VERSION 5.7 ;
  NOWIREEXTENSIONATPIN ON ;
  DIVIDERCHAR "/" ;
  BUSBITCHARS "[]" ;
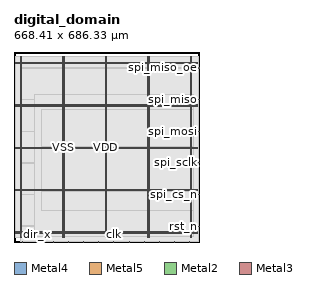
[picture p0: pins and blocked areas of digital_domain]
MACRO digital_domain
  CLASS BLOCK ;
  FOREIGN digital_domain ;
  ORIGIN 0.000 0.000 ;
  SIZE 668.410 BY 686.330 ;
  PIN VDD
    DIRECTION INOUT ;
    USE POWER ;
    PORT
      LAYER Metal4 ;
        RECT 22.240 15.380 23.840 670.620 ;
    END
    PORT
      LAYER Metal4 ;
        RECT 175.840 15.380 177.440 670.620 ;
    END
    PORT
      LAYER Metal4 ;
        RECT 329.440 15.380 331.040 670.620 ;
    END
    PORT
      LAYER Metal4 ;
        RECT 483.040 15.380 484.640 670.620 ;
    END
    PORT
      LAYER Metal4 ;
        RECT 636.640 15.380 638.240 670.620 ;
    END
    PORT
      LAYER Metal5 ;
        RECT 6.720 31.530 661.360 33.130 ;
    END
    PORT
      LAYER Metal5 ;
        RECT 6.720 184.710 661.360 186.310 ;
    END
    PORT
      LAYER Metal5 ;
        RECT 6.720 337.890 661.360 339.490 ;
    END
    PORT
      LAYER Metal5 ;
        RECT 6.720 491.070 661.360 492.670 ;
    END
    PORT
      LAYER Metal5 ;
        RECT 6.720 644.250 661.360 645.850 ;
    END
  END VDD
  PIN VSS
    DIRECTION INOUT ;
    USE GROUND ;
    PORT
      LAYER Metal4 ;
        RECT 25.540 15.380 27.140 670.620 ;
    END
    PORT
      LAYER Metal4 ;
        RECT 179.140 15.380 180.740 670.620 ;
    END
    PORT
      LAYER Metal4 ;
        RECT 332.740 15.380 334.340 670.620 ;
    END
    PORT
      LAYER Metal4 ;
        RECT 486.340 15.380 487.940 670.620 ;
    END
    PORT
      LAYER Metal4 ;
        RECT 639.940 15.380 641.540 670.620 ;
    END
    PORT
      LAYER Metal5 ;
        RECT 6.720 34.830 661.360 36.430 ;
    END
    PORT
      LAYER Metal5 ;
        RECT 6.720 188.010 661.360 189.610 ;
    END
    PORT
      LAYER Metal5 ;
        RECT 6.720 341.190 661.360 342.790 ;
    END
    PORT
      LAYER Metal5 ;
        RECT 6.720 494.370 661.360 495.970 ;
    END
    PORT
      LAYER Metal5 ;
        RECT 6.720 647.550 661.360 649.150 ;
    END
  END VSS
  PIN clk
    DIRECTION INPUT ;
    USE SIGNAL ;
    ANTENNAGATEAREA 4.738000 ;
    PORT
      LAYER Metal2 ;
        RECT 360.640 0.000 361.200 0.560 ;
    END
  END clk
  PIN comp_x
    DIRECTION INPUT ;
    USE SIGNAL ;
    ANTENNAGATEAREA 0.498500 ;
    PORT
      LAYER Metal2 ;
        RECT 250.880 0.000 251.440 0.560 ;
    END
  END comp_x
  PIN comp_y
    DIRECTION INPUT ;
    USE SIGNAL ;
    ANTENNAGATEAREA 0.498500 ;
    PORT
      LAYER Metal2 ;
        RECT 415.520 0.000 416.080 0.560 ;
    END
  END comp_y
  PIN dir_x
    DIRECTION OUTPUT ;
    USE SIGNAL ;
    ANTENNADIFFAREA 1.182800 ;
    PORT
      LAYER Metal2 ;
        RECT 86.240 0.000 86.800 0.560 ;
    END
  END dir_x
  PIN dir_y
    DIRECTION OUTPUT ;
    USE SIGNAL ;
    ANTENNADIFFAREA 1.182800 ;
    PORT
      LAYER Metal2 ;
        RECT 580.160 0.000 580.720 0.560 ;
    END
  END dir_y
  PIN mems_drv_x
    DIRECTION OUTPUT ;
    USE SIGNAL ;
    ANTENNADIFFAREA 1.182800 ;
    PORT
      LAYER Metal2 ;
        RECT 141.120 0.000 141.680 0.560 ;
    END
  END mems_drv_x
  PIN mems_drv_y
    DIRECTION OUTPUT ;
    USE SIGNAL ;
    ANTENNADIFFAREA 1.182800 ;
    PORT
      LAYER Metal2 ;
        RECT 525.280 0.000 525.840 0.560 ;
    END
  END mems_drv_y
  PIN move_en_x
    DIRECTION OUTPUT ;
    USE SIGNAL ;
    ANTENNADIFFAREA 1.182800 ;
    PORT
      LAYER Metal2 ;
        RECT 31.360 0.000 31.920 0.560 ;
    END
  END move_en_x
  PIN move_en_y
    DIRECTION OUTPUT ;
    USE SIGNAL ;
    ANTENNADIFFAREA 1.182800 ;
    PORT
      LAYER Metal2 ;
        RECT 635.040 0.000 635.600 0.560 ;
    END
  END move_en_y
  PIN read_en
    DIRECTION OUTPUT ;
    USE SIGNAL ;
    ANTENNADIFFAREA 1.182800 ;
    PORT
      LAYER Metal2 ;
        RECT 305.760 0.000 306.320 0.560 ;
    END
  END read_en
  PIN ref_wave_x
    DIRECTION OUTPUT ;
    USE SIGNAL ;
    ANTENNADIFFAREA 1.182800 ;
    PORT
      LAYER Metal2 ;
        RECT 196.000 0.000 196.560 0.560 ;
    END
  END ref_wave_x
  PIN ref_wave_y
    DIRECTION OUTPUT ;
    USE SIGNAL ;
    ANTENNADIFFAREA 1.182800 ;
    PORT
      LAYER Metal2 ;
        RECT 470.400 0.000 470.960 0.560 ;
    END
  END ref_wave_y
  PIN rst_n
    DIRECTION INPUT ;
    USE SIGNAL ;
    ANTENNAGATEAREA 0.498500 ;
    PORT
      LAYER Metal3 ;
        RECT 667.850 57.120 668.410 57.680 ;
    END
  END rst_n
  PIN spi_cs_n
    DIRECTION INPUT ;
    USE SIGNAL ;
    ANTENNAGATEAREA 0.498500 ;
    PORT
      LAYER Metal3 ;
        RECT 667.850 171.360 668.410 171.920 ;
    END
  END spi_cs_n
  PIN spi_miso
    DIRECTION OUTPUT ;
    USE SIGNAL ;
    ANTENNADIFFAREA 1.182800 ;
    PORT
      LAYER Metal3 ;
        RECT 667.850 514.080 668.410 514.640 ;
    END
  END spi_miso
  PIN spi_miso_oe
    DIRECTION OUTPUT ;
    USE SIGNAL ;
    ANTENNADIFFAREA 1.182800 ;
    PORT
      LAYER Metal3 ;
        RECT 667.850 628.320 668.410 628.880 ;
    END
  END spi_miso_oe
  PIN spi_mosi
    DIRECTION INPUT ;
    USE SIGNAL ;
    ANTENNAGATEAREA 0.498500 ;
    PORT
      LAYER Metal3 ;
        RECT 667.850 399.840 668.410 400.400 ;
    END
  END spi_mosi
  PIN spi_sclk
    DIRECTION INPUT ;
    USE SIGNAL ;
    ANTENNAGATEAREA 0.498500 ;
    PORT
      LAYER Metal3 ;
        RECT 667.850 285.600 668.410 286.160 ;
    END
  END spi_sclk
  OBS
      LAYER Nwell ;
        RECT 6.290 668.160 661.790 670.750 ;
      LAYER Pwell ;
        RECT 6.290 664.640 661.790 668.160 ;
      LAYER Nwell ;
        RECT 6.290 660.320 661.790 664.640 ;
      LAYER Pwell ;
        RECT 6.290 656.800 661.790 660.320 ;
      LAYER Nwell ;
        RECT 6.290 652.480 661.790 656.800 ;
      LAYER Pwell ;
        RECT 6.290 648.960 661.790 652.480 ;
      LAYER Nwell ;
        RECT 6.290 644.640 661.790 648.960 ;
      LAYER Pwell ;
        RECT 6.290 641.120 661.790 644.640 ;
      LAYER Nwell ;
        RECT 6.290 636.800 661.790 641.120 ;
      LAYER Pwell ;
        RECT 6.290 633.280 661.790 636.800 ;
      LAYER Nwell ;
        RECT 6.290 628.960 661.790 633.280 ;
      LAYER Pwell ;
        RECT 6.290 625.440 661.790 628.960 ;
      LAYER Nwell ;
        RECT 6.290 621.120 661.790 625.440 ;
      LAYER Pwell ;
        RECT 6.290 617.600 661.790 621.120 ;
      LAYER Nwell ;
        RECT 6.290 613.280 661.790 617.600 ;
      LAYER Pwell ;
        RECT 6.290 609.760 661.790 613.280 ;
      LAYER Nwell ;
        RECT 6.290 605.440 661.790 609.760 ;
      LAYER Pwell ;
        RECT 6.290 601.920 661.790 605.440 ;
      LAYER Nwell ;
        RECT 6.290 597.600 661.790 601.920 ;
      LAYER Pwell ;
        RECT 6.290 594.080 661.790 597.600 ;
      LAYER Nwell ;
        RECT 6.290 589.760 661.790 594.080 ;
      LAYER Pwell ;
        RECT 6.290 586.240 661.790 589.760 ;
      LAYER Nwell ;
        RECT 6.290 581.920 661.790 586.240 ;
      LAYER Pwell ;
        RECT 6.290 578.400 661.790 581.920 ;
      LAYER Nwell ;
        RECT 6.290 574.080 661.790 578.400 ;
      LAYER Pwell ;
        RECT 6.290 570.560 661.790 574.080 ;
      LAYER Nwell ;
        RECT 6.290 566.240 661.790 570.560 ;
      LAYER Pwell ;
        RECT 6.290 562.720 661.790 566.240 ;
      LAYER Nwell ;
        RECT 6.290 558.400 661.790 562.720 ;
      LAYER Pwell ;
        RECT 6.290 554.880 661.790 558.400 ;
      LAYER Nwell ;
        RECT 6.290 550.560 661.790 554.880 ;
      LAYER Pwell ;
        RECT 6.290 547.040 661.790 550.560 ;
      LAYER Nwell ;
        RECT 6.290 542.720 661.790 547.040 ;
      LAYER Pwell ;
        RECT 6.290 539.200 661.790 542.720 ;
      LAYER Nwell ;
        RECT 6.290 534.880 661.790 539.200 ;
      LAYER Pwell ;
        RECT 6.290 531.360 661.790 534.880 ;
      LAYER Nwell ;
        RECT 6.290 527.040 661.790 531.360 ;
      LAYER Pwell ;
        RECT 6.290 523.520 661.790 527.040 ;
      LAYER Nwell ;
        RECT 6.290 519.200 661.790 523.520 ;
      LAYER Pwell ;
        RECT 6.290 515.680 661.790 519.200 ;
      LAYER Nwell ;
        RECT 6.290 511.360 661.790 515.680 ;
      LAYER Pwell ;
        RECT 6.290 507.840 661.790 511.360 ;
      LAYER Nwell ;
        RECT 6.290 503.520 661.790 507.840 ;
      LAYER Pwell ;
        RECT 6.290 500.000 661.790 503.520 ;
      LAYER Nwell ;
        RECT 6.290 495.680 661.790 500.000 ;
      LAYER Pwell ;
        RECT 6.290 492.160 661.790 495.680 ;
      LAYER Nwell ;
        RECT 6.290 487.840 661.790 492.160 ;
      LAYER Pwell ;
        RECT 6.290 484.320 661.790 487.840 ;
      LAYER Nwell ;
        RECT 6.290 480.000 661.790 484.320 ;
      LAYER Pwell ;
        RECT 6.290 476.480 661.790 480.000 ;
      LAYER Nwell ;
        RECT 6.290 472.160 661.790 476.480 ;
      LAYER Pwell ;
        RECT 6.290 468.640 661.790 472.160 ;
      LAYER Nwell ;
        RECT 6.290 464.320 661.790 468.640 ;
      LAYER Pwell ;
        RECT 6.290 460.800 661.790 464.320 ;
      LAYER Nwell ;
        RECT 6.290 456.480 661.790 460.800 ;
      LAYER Pwell ;
        RECT 6.290 452.960 661.790 456.480 ;
      LAYER Nwell ;
        RECT 6.290 448.640 661.790 452.960 ;
      LAYER Pwell ;
        RECT 6.290 445.120 661.790 448.640 ;
      LAYER Nwell ;
        RECT 6.290 440.800 661.790 445.120 ;
      LAYER Pwell ;
        RECT 6.290 437.280 661.790 440.800 ;
      LAYER Nwell ;
        RECT 6.290 432.960 661.790 437.280 ;
      LAYER Pwell ;
        RECT 6.290 429.440 661.790 432.960 ;
      LAYER Nwell ;
        RECT 6.290 425.120 661.790 429.440 ;
      LAYER Pwell ;
        RECT 6.290 421.600 661.790 425.120 ;
      LAYER Nwell ;
        RECT 6.290 417.280 661.790 421.600 ;
      LAYER Pwell ;
        RECT 6.290 413.760 661.790 417.280 ;
      LAYER Nwell ;
        RECT 6.290 409.440 661.790 413.760 ;
      LAYER Pwell ;
        RECT 6.290 405.920 661.790 409.440 ;
      LAYER Nwell ;
        RECT 6.290 401.600 661.790 405.920 ;
      LAYER Pwell ;
        RECT 6.290 398.080 661.790 401.600 ;
      LAYER Nwell ;
        RECT 6.290 393.760 661.790 398.080 ;
      LAYER Pwell ;
        RECT 6.290 390.240 661.790 393.760 ;
      LAYER Nwell ;
        RECT 6.290 385.920 661.790 390.240 ;
      LAYER Pwell ;
        RECT 6.290 382.400 661.790 385.920 ;
      LAYER Nwell ;
        RECT 6.290 378.080 661.790 382.400 ;
      LAYER Pwell ;
        RECT 6.290 374.560 661.790 378.080 ;
      LAYER Nwell ;
        RECT 6.290 370.240 661.790 374.560 ;
      LAYER Pwell ;
        RECT 6.290 366.720 661.790 370.240 ;
      LAYER Nwell ;
        RECT 6.290 362.400 661.790 366.720 ;
      LAYER Pwell ;
        RECT 6.290 358.880 661.790 362.400 ;
      LAYER Nwell ;
        RECT 6.290 354.560 661.790 358.880 ;
      LAYER Pwell ;
        RECT 6.290 351.040 661.790 354.560 ;
      LAYER Nwell ;
        RECT 6.290 346.720 661.790 351.040 ;
      LAYER Pwell ;
        RECT 6.290 343.200 661.790 346.720 ;
      LAYER Nwell ;
        RECT 6.290 338.880 661.790 343.200 ;
      LAYER Pwell ;
        RECT 6.290 335.360 661.790 338.880 ;
      LAYER Nwell ;
        RECT 6.290 331.040 661.790 335.360 ;
      LAYER Pwell ;
        RECT 6.290 327.520 661.790 331.040 ;
      LAYER Nwell ;
        RECT 6.290 323.200 661.790 327.520 ;
      LAYER Pwell ;
        RECT 6.290 319.680 661.790 323.200 ;
      LAYER Nwell ;
        RECT 6.290 315.360 661.790 319.680 ;
      LAYER Pwell ;
        RECT 6.290 311.840 661.790 315.360 ;
      LAYER Nwell ;
        RECT 6.290 307.520 661.790 311.840 ;
      LAYER Pwell ;
        RECT 6.290 304.000 661.790 307.520 ;
      LAYER Nwell ;
        RECT 6.290 299.680 661.790 304.000 ;
      LAYER Pwell ;
        RECT 6.290 296.160 661.790 299.680 ;
      LAYER Nwell ;
        RECT 6.290 291.840 661.790 296.160 ;
      LAYER Pwell ;
        RECT 6.290 288.320 661.790 291.840 ;
      LAYER Nwell ;
        RECT 6.290 284.000 661.790 288.320 ;
      LAYER Pwell ;
        RECT 6.290 280.480 661.790 284.000 ;
      LAYER Nwell ;
        RECT 6.290 276.160 661.790 280.480 ;
      LAYER Pwell ;
        RECT 6.290 272.640 661.790 276.160 ;
      LAYER Nwell ;
        RECT 6.290 268.320 661.790 272.640 ;
      LAYER Pwell ;
        RECT 6.290 264.800 661.790 268.320 ;
      LAYER Nwell ;
        RECT 6.290 260.480 661.790 264.800 ;
      LAYER Pwell ;
        RECT 6.290 256.960 661.790 260.480 ;
      LAYER Nwell ;
        RECT 6.290 252.640 661.790 256.960 ;
      LAYER Pwell ;
        RECT 6.290 249.120 661.790 252.640 ;
      LAYER Nwell ;
        RECT 6.290 244.800 661.790 249.120 ;
      LAYER Pwell ;
        RECT 6.290 241.280 661.790 244.800 ;
      LAYER Nwell ;
        RECT 6.290 236.960 661.790 241.280 ;
      LAYER Pwell ;
        RECT 6.290 233.440 661.790 236.960 ;
      LAYER Nwell ;
        RECT 6.290 229.120 661.790 233.440 ;
      LAYER Pwell ;
        RECT 6.290 225.600 661.790 229.120 ;
      LAYER Nwell ;
        RECT 6.290 221.280 661.790 225.600 ;
      LAYER Pwell ;
        RECT 6.290 217.760 661.790 221.280 ;
      LAYER Nwell ;
        RECT 6.290 213.440 661.790 217.760 ;
      LAYER Pwell ;
        RECT 6.290 209.920 661.790 213.440 ;
      LAYER Nwell ;
        RECT 6.290 205.600 661.790 209.920 ;
      LAYER Pwell ;
        RECT 6.290 202.080 661.790 205.600 ;
      LAYER Nwell ;
        RECT 6.290 197.760 661.790 202.080 ;
      LAYER Pwell ;
        RECT 6.290 194.240 661.790 197.760 ;
      LAYER Nwell ;
        RECT 6.290 189.920 661.790 194.240 ;
      LAYER Pwell ;
        RECT 6.290 186.400 661.790 189.920 ;
      LAYER Nwell ;
        RECT 6.290 182.080 661.790 186.400 ;
      LAYER Pwell ;
        RECT 6.290 178.560 661.790 182.080 ;
      LAYER Nwell ;
        RECT 6.290 174.240 661.790 178.560 ;
      LAYER Pwell ;
        RECT 6.290 170.720 661.790 174.240 ;
      LAYER Nwell ;
        RECT 6.290 166.400 661.790 170.720 ;
      LAYER Pwell ;
        RECT 6.290 162.880 661.790 166.400 ;
      LAYER Nwell ;
        RECT 6.290 158.560 661.790 162.880 ;
      LAYER Pwell ;
        RECT 6.290 155.040 661.790 158.560 ;
      LAYER Nwell ;
        RECT 6.290 150.720 661.790 155.040 ;
      LAYER Pwell ;
        RECT 6.290 147.200 661.790 150.720 ;
      LAYER Nwell ;
        RECT 6.290 142.880 661.790 147.200 ;
      LAYER Pwell ;
        RECT 6.290 139.360 661.790 142.880 ;
      LAYER Nwell ;
        RECT 6.290 135.040 661.790 139.360 ;
      LAYER Pwell ;
        RECT 6.290 131.520 661.790 135.040 ;
      LAYER Nwell ;
        RECT 6.290 127.200 661.790 131.520 ;
      LAYER Pwell ;
        RECT 6.290 123.680 661.790 127.200 ;
      LAYER Nwell ;
        RECT 6.290 119.360 661.790 123.680 ;
      LAYER Pwell ;
        RECT 6.290 115.840 661.790 119.360 ;
      LAYER Nwell ;
        RECT 6.290 111.520 661.790 115.840 ;
      LAYER Pwell ;
        RECT 6.290 108.000 661.790 111.520 ;
      LAYER Nwell ;
        RECT 6.290 103.680 661.790 108.000 ;
      LAYER Pwell ;
        RECT 6.290 100.160 661.790 103.680 ;
      LAYER Nwell ;
        RECT 6.290 95.840 661.790 100.160 ;
      LAYER Pwell ;
        RECT 6.290 92.320 661.790 95.840 ;
      LAYER Nwell ;
        RECT 6.290 88.000 661.790 92.320 ;
      LAYER Pwell ;
        RECT 6.290 84.480 661.790 88.000 ;
      LAYER Nwell ;
        RECT 6.290 80.160 661.790 84.480 ;
      LAYER Pwell ;
        RECT 6.290 76.640 661.790 80.160 ;
      LAYER Nwell ;
        RECT 6.290 72.320 661.790 76.640 ;
      LAYER Pwell ;
        RECT 6.290 68.800 661.790 72.320 ;
      LAYER Nwell ;
        RECT 6.290 64.480 661.790 68.800 ;
      LAYER Pwell ;
        RECT 6.290 60.960 661.790 64.480 ;
      LAYER Nwell ;
        RECT 6.290 56.640 661.790 60.960 ;
      LAYER Pwell ;
        RECT 6.290 53.120 661.790 56.640 ;
      LAYER Nwell ;
        RECT 6.290 48.800 661.790 53.120 ;
      LAYER Pwell ;
        RECT 6.290 45.280 661.790 48.800 ;
      LAYER Nwell ;
        RECT 6.290 40.960 661.790 45.280 ;
      LAYER Pwell ;
        RECT 6.290 37.440 661.790 40.960 ;
      LAYER Nwell ;
        RECT 6.290 33.120 661.790 37.440 ;
      LAYER Pwell ;
        RECT 6.290 29.600 661.790 33.120 ;
      LAYER Nwell ;
        RECT 6.290 25.280 661.790 29.600 ;
      LAYER Pwell ;
        RECT 6.290 21.760 661.790 25.280 ;
      LAYER Nwell ;
        RECT 6.290 17.440 661.790 21.760 ;
      LAYER Pwell ;
        RECT 6.290 15.250 661.790 17.440 ;
      LAYER Metal1 ;
        RECT 6.720 15.380 661.360 670.620 ;
      LAYER Metal2 ;
        RECT 22.380 0.860 660.660 670.510 ;
        RECT 22.380 0.140 31.060 0.860 ;
        RECT 32.220 0.140 85.940 0.860 ;
        RECT 87.100 0.140 140.820 0.860 ;
        RECT 141.980 0.140 195.700 0.860 ;
        RECT 196.860 0.140 250.580 0.860 ;
        RECT 251.740 0.140 305.460 0.860 ;
        RECT 306.620 0.140 360.340 0.860 ;
        RECT 361.500 0.140 415.220 0.860 ;
        RECT 416.380 0.140 470.100 0.860 ;
        RECT 471.260 0.140 524.980 0.860 ;
        RECT 526.140 0.140 579.860 0.860 ;
        RECT 581.020 0.140 634.740 0.860 ;
        RECT 635.900 0.140 660.660 0.860 ;
      LAYER Metal3 ;
        RECT 22.330 629.180 667.850 670.460 ;
        RECT 22.330 628.020 667.550 629.180 ;
        RECT 22.330 514.940 667.850 628.020 ;
        RECT 22.330 513.780 667.550 514.940 ;
        RECT 22.330 400.700 667.850 513.780 ;
        RECT 22.330 399.540 667.550 400.700 ;
        RECT 22.330 286.460 667.850 399.540 ;
        RECT 22.330 285.300 667.550 286.460 ;
        RECT 22.330 172.220 667.850 285.300 ;
        RECT 22.330 171.060 667.550 172.220 ;
        RECT 22.330 57.980 667.850 171.060 ;
        RECT 22.330 56.820 667.550 57.980 ;
        RECT 22.330 0.700 667.850 56.820 ;
      LAYER Metal4 ;
        RECT 75.740 20.250 175.540 531.910 ;
        RECT 177.740 20.250 178.840 531.910 ;
        RECT 181.040 20.250 329.140 531.910 ;
        RECT 331.340 20.250 332.440 531.910 ;
        RECT 334.640 20.250 482.740 531.910 ;
        RECT 484.940 20.250 486.040 531.910 ;
        RECT 488.240 20.250 636.340 531.910 ;
        RECT 638.540 20.250 639.640 531.910 ;
        RECT 641.840 20.250 650.020 531.910 ;
      LAYER Metal5 ;
        RECT 98.620 343.390 650.100 479.470 ;
        RECT 98.620 340.090 650.100 340.590 ;
        RECT 98.620 190.210 650.100 337.290 ;
        RECT 98.620 186.910 650.100 187.410 ;
        RECT 98.620 112.730 650.100 184.110 ;
  END
END digital_domain
END LIBRARY

